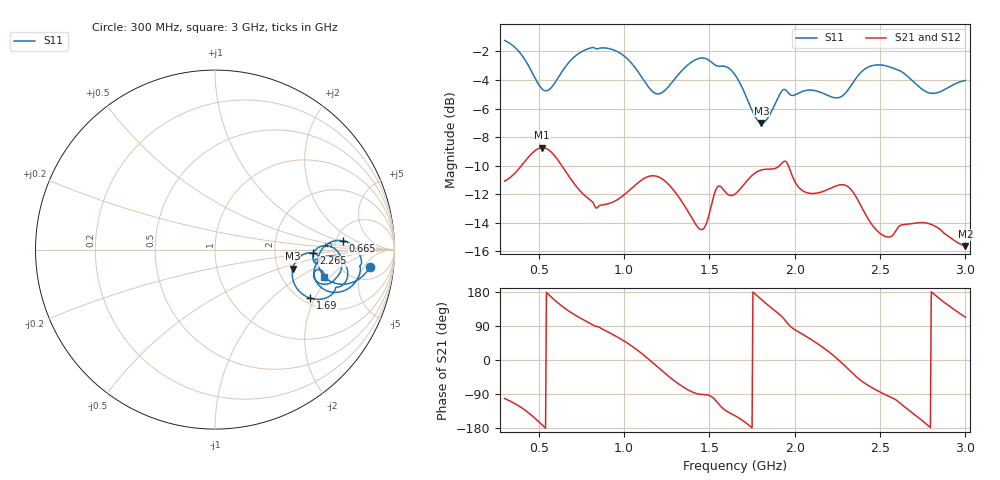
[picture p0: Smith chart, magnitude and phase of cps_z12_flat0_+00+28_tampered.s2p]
! cps_z12_flat0_+00+28_tampered
! simulated by sim/fixtures_fdtd.py (S12 = S21, S22 not computed)
# HZ S RI R 50
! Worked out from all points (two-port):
!   541 points, 300 MHz to 3 GHz, reference 50 ohm
!   highest |S21| = -8.74 dB at 520 MHz (marker M1); lowest = -15.7 dB at 3 GHz (marker M2)
!   |S21| within 3 dB of the highest: start of sweep to 739.9 MHz; 1.673 GHz to 2.044 GHz (371 MHz wide, 20 % of centre) (the widest 2 of 5)
!   lowest |S11| = -7.0 dB at 1.805 GHz (marker M3), VSWR 2.61, Z = 120 - j32.2 ohm
!   |S11| at or under -10 dB: nowhere
!   |S22| runs from - to - dB; largest |S21 - S12| = 0
!   S11 on the Smith chart (normalised r, x): 300 MHz: 9, -7; 665 MHz: 5.74, +1.15; 1.69 GHz: 2.20, -1.85; 2.265 GHz: 3.42, -0.20; 3 GHz: 3.46, -1.73
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3e8  0.8625 -0.0979  -0.0563 -0.2734  -0.0563 -0.2734  0 0
4.25e8  0.7076 -0.1931  -0.2298 -0.2376  -0.2298 -0.2376  0 0
5.2e8  0.5787 -0.0955  -0.3612 -0.0557  -0.3612 -0.0557  0 0
6.65e8  0.7116 0.0492  -0.2016 0.2183  -0.2016 0.2183  0 0
7.5e8  0.7922 -0.00353  -0.0832 0.2409  -0.0832 0.2409  0 0
9e8  0.803 -0.1434  0.0586 0.2243  0.0586 0.2243  0 0
1.035e9  0.693 -0.2364  0.1995 0.167  0.1995 0.167  0 0
1.2e9  0.5537 -0.1075  0.2716 -0.0985  0.2716 -0.0985  0 0
1.31e9  0.6496 -0.0346  0.1254 -0.2166  0.1254 -0.2166  0 0
1.435e9  0.7395 -0.1237  0.00122 -0.1915  0.00122 -0.1915  0 0
1.545e9  0.6752 -0.2089  -0.0961 -0.247  -0.0961 -0.247  0 0
1.65e9  0.5974 -0.2752  -0.2109 -0.1366  -0.2109 -0.1366  0 0
1.69e9  0.5318 -0.2709  -0.2467 -0.0992  -0.2467 -0.0992  0 0
1.805e9  0.4331 -0.107  -0.2862 0.1063  -0.2862 0.1063  0 0
1.885e9  0.5201 -0.0179  -0.1974 0.2377  -0.1974 0.2377  0 0
1.95e9  0.5759 -0.0719  -0.0621 0.3201  -0.0621 0.3201  0 0
2.1e9  0.5771 -0.0699  0.1524 0.2013  0.1524 0.2013  0 0
2.265e9  0.5485 -0.0203  0.2703 -0.0148  0.2703 -0.0148  0 0
2.375e9  0.6582 0.0108  0.1534 -0.1798  0.1534 -0.1798  0 0
2.55e9  0.6887 -0.1416  -0.0173 -0.1767  -0.0173 -0.1767  0 0
2.78e9  0.5502 -0.1506  -0.1967 -0.0259  -0.1967 -0.0259  0 0
3e9  0.61 -0.1516  -0.0646 0.1518  -0.0646 0.1518  0 0
